# mini45 technology LEF: a made-up 45 nm-class stack for testing tools.
# Generated by gen_mini45.py; do not edit.
VERSION 5.8 ;
BUSBITCHARS "[]" ;
DIVIDERCHAR "/" ;

UNITS
  TIME NANOSECONDS 1 ;
  CAPACITANCE PICOFARADS 1 ;
  RESISTANCE OHMS 1 ;
  DATABASE MICRONS 2000 ;
END UNITS

MANUFACTURINGGRID 0.005 ;

SITE core
  CLASS CORE ;
  SYMMETRY Y ;
  SIZE 0.19 BY 1.40 ;
END core

LAYER poly
  TYPE MASTERSLICE ;
END poly

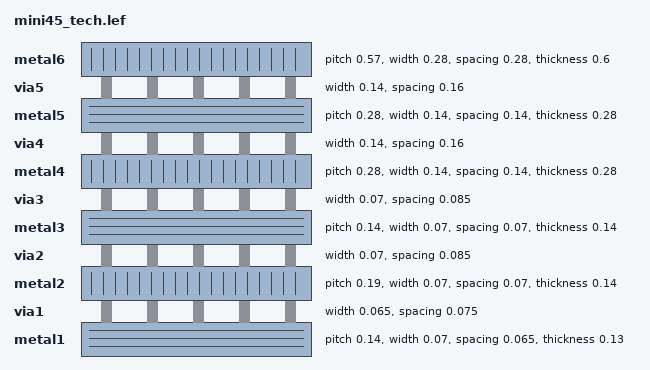
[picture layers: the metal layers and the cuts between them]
LAYER metal1
  TYPE ROUTING ;
  DIRECTION HORIZONTAL ;
  PITCH 0.140 ;
  OFFSET 0.000 ;
  WIDTH 0.070 ;
  SPACING 0.065 ;
  AREA 0.0147 ;
  RESISTANCE RPERSQ 0.380 ;
  CAPACITANCE CPERSQDIST 7.700e-05 ;
  EDGECAPACITANCE 2.700e-05 ;
  THICKNESS 0.13 ;
  HEIGHT 0.37 ;
END metal1

LAYER via1
  TYPE CUT ;
  WIDTH 0.065 ;
  SPACING 0.075 ;
  RESISTANCE 5.0 ;
END via1

LAYER metal2
  TYPE ROUTING ;
  DIRECTION VERTICAL ;
  PITCH 0.190 ;
  OFFSET 0.095 ;
  WIDTH 0.070 ;
  SPACING 0.070 ;
  AREA 0.0147 ;
  RESISTANCE RPERSQ 0.250 ;
  CAPACITANCE CPERSQDIST 4.000e-05 ;
  EDGECAPACITANCE 2.500e-05 ;
  THICKNESS 0.14 ;
  HEIGHT 0.62 ;
END metal2

LAYER via2
  TYPE CUT ;
  WIDTH 0.070 ;
  SPACING 0.085 ;
  RESISTANCE 5.0 ;
END via2

LAYER metal3
  TYPE ROUTING ;
  DIRECTION HORIZONTAL ;
  PITCH 0.140 ;
  OFFSET 0.000 ;
  WIDTH 0.070 ;
  SPACING 0.070 ;
  AREA 0.0147 ;
  RESISTANCE RPERSQ 0.250 ;
  CAPACITANCE CPERSQDIST 2.700e-05 ;
  EDGECAPACITANCE 2.500e-05 ;
  THICKNESS 0.14 ;
  HEIGHT 0.88 ;
END metal3

LAYER via3
  TYPE CUT ;
  WIDTH 0.070 ;
  SPACING 0.085 ;
  RESISTANCE 5.0 ;
END via3

LAYER metal4
  TYPE ROUTING ;
  DIRECTION VERTICAL ;
  PITCH 0.280 ;
  OFFSET 0.140 ;
  WIDTH 0.140 ;
  SPACING 0.140 ;
  AREA 0.0588 ;
  RESISTANCE RPERSQ 0.210 ;
  CAPACITANCE CPERSQDIST 2.000e-05 ;
  EDGECAPACITANCE 2.300e-05 ;
  THICKNESS 0.28 ;
  HEIGHT 1.14 ;
END metal4

LAYER via4
  TYPE CUT ;
  WIDTH 0.140 ;
  SPACING 0.160 ;
  RESISTANCE 3.0 ;
END via4

LAYER metal5
  TYPE ROUTING ;
  DIRECTION HORIZONTAL ;
  PITCH 0.280 ;
  OFFSET 0.000 ;
  WIDTH 0.140 ;
  SPACING 0.140 ;
  AREA 0.0588 ;
  RESISTANCE RPERSQ 0.210 ;
  CAPACITANCE CPERSQDIST 1.600e-05 ;
  EDGECAPACITANCE 2.300e-05 ;
  THICKNESS 0.28 ;
  HEIGHT 1.54 ;
END metal5

LAYER via5
  TYPE CUT ;
  WIDTH 0.140 ;
  SPACING 0.160 ;
  RESISTANCE 3.0 ;
END via5

LAYER metal6
  TYPE ROUTING ;
  DIRECTION VERTICAL ;
  PITCH 0.570 ;
  OFFSET 0.285 ;
  WIDTH 0.280 ;
  SPACING 0.280 ;
  AREA 0.2352 ;
  RESISTANCE RPERSQ 0.080 ;
  CAPACITANCE CPERSQDIST 1.200e-05 ;
  EDGECAPACITANCE 2.000e-05 ;
  THICKNESS 0.60 ;
  HEIGHT 1.94 ;
END metal6

LAYER OVERLAP
  TYPE OVERLAP ;
END OVERLAP

VIA via1_0 DEFAULT
  RESISTANCE 5.0 ;
  LAYER metal1 ;
    RECT -0.083 -0.035 0.083 0.035 ;
  LAYER via1 ;
    RECT -0.0325 -0.0325 0.0325 0.0325 ;
  LAYER metal2 ;
    RECT -0.035 -0.083 0.035 0.083 ;
END via1_0

VIA via1_1 DEFAULT
  RESISTANCE 5.0 ;
  LAYER metal1 ;
    RECT -0.035 -0.105 0.035 0.105 ;
  LAYER via1 ;
    RECT -0.0325 -0.0325 0.0325 0.0325 ;
  LAYER metal2 ;
    RECT -0.035 -0.083 0.035 0.083 ;
END via1_1

VIA via2_0 DEFAULT
  RESISTANCE 5.0 ;
  LAYER metal2 ;
    RECT -0.035 -0.085 0.035 0.085 ;
  LAYER via2 ;
    RECT -0.0350 -0.0350 0.0350 0.0350 ;
  LAYER metal3 ;
    RECT -0.085 -0.035 0.085 0.035 ;
END via2_0

VIA via3_0 DEFAULT
  RESISTANCE 5.0 ;
  LAYER metal3 ;
    RECT -0.085 -0.035 0.085 0.035 ;
  LAYER via3 ;
    RECT -0.0350 -0.0350 0.0350 0.0350 ;
  LAYER metal4 ;
    RECT -0.070 -0.100 0.070 0.100 ;
END via3_0

VIA via4_0 DEFAULT
  RESISTANCE 3.0 ;
  LAYER metal4 ;
    RECT -0.070 -0.120 0.070 0.120 ;
  LAYER via4 ;
    RECT -0.0700 -0.0700 0.0700 0.0700 ;
  LAYER metal5 ;
    RECT -0.120 -0.070 0.120 0.070 ;
END via4_0

VIA via5_0 DEFAULT
  RESISTANCE 3.0 ;
  LAYER metal5 ;
    RECT -0.120 -0.070 0.120 0.070 ;
  LAYER via5 ;
    RECT -0.0700 -0.0700 0.0700 0.0700 ;
  LAYER metal6 ;
    RECT -0.140 -0.170 0.140 0.170 ;
END via5_0

END LIBRARY
